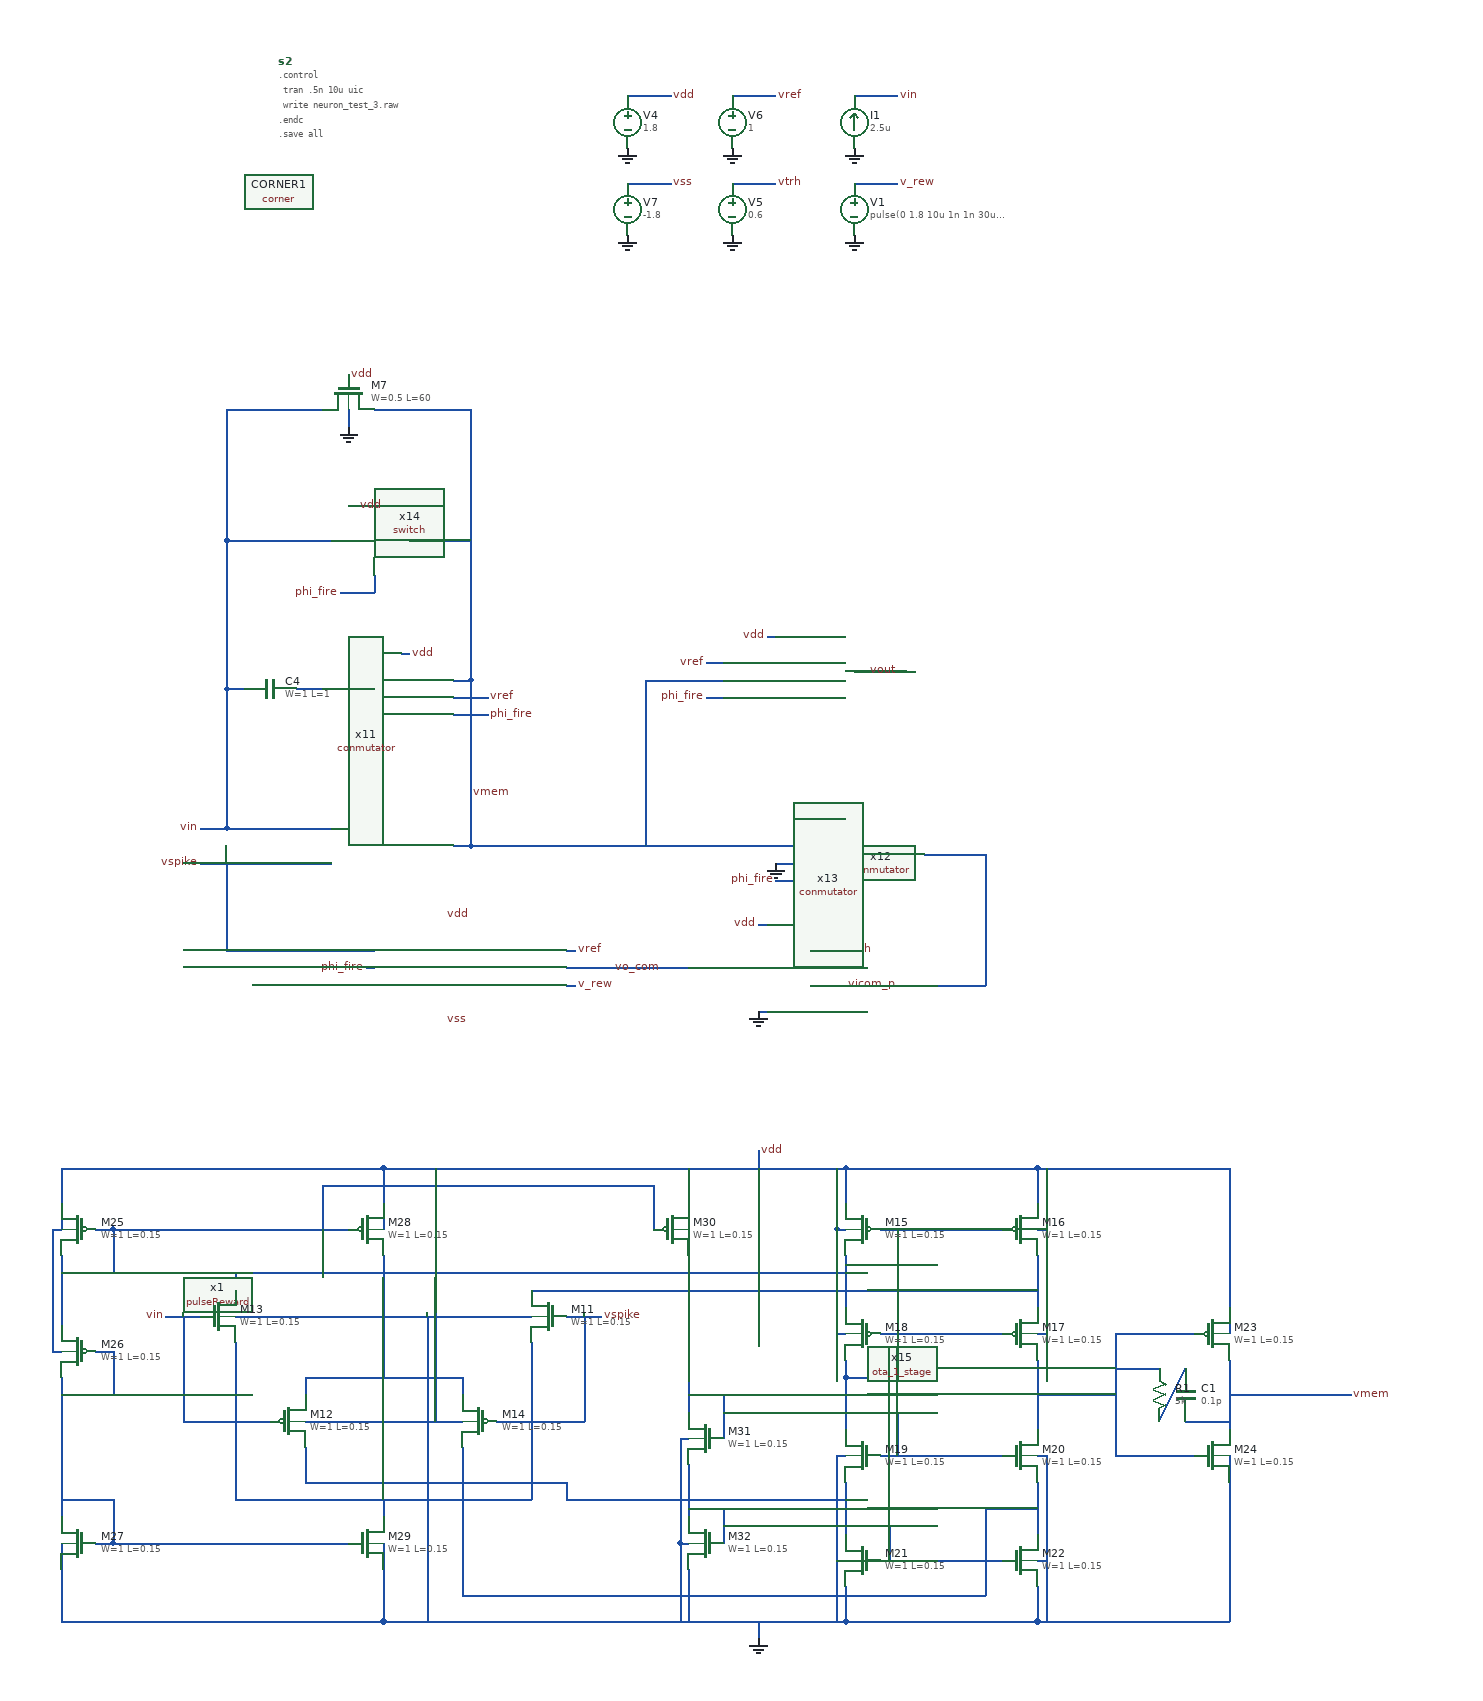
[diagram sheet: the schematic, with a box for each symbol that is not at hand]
v {xschem version=3.4.5 file_version=1.2
}
G {}
K {}
V {}
S {}
E {}
B 2 -940 -540 -140 -140 {flags=graph
y1=0.6
y2=1.5
ypos1=0
ypos2=2
divy=5
subdivy=1
unity=1
x1=5e-12
x2=1e-05
divx=5
subdivx=1


dataset=-1
unitx=1
logx=0
logy=0
color=12
node=vout}
B 2 -940 -1340 -140 -940 {flags=graph
y1=0.075
y2=1.8
ypos1=0
ypos2=2
divy=5
subdivy=1
unity=1
x1=5e-12
x2=1e-05
divx=5
subdivx=1


dataset=-1
unitx=1
logx=0
logy=0
color=7
node=vmem}
B 2 -940 -1740 -140 -1340 {flags=graph
y1=0.26

ypos1=0
ypos2=2
divy=5
subdivy=1
unity=1
x1=5e-12
x2=1e-05
divx=5
subdivx=1


dataset=-1
unitx=1
logx=0
logy=0
color=4
node=vspike
y2=1.6}
B 2 -940 -940 -140 -540 {flags=graph
y1=0.085
y2=2.1
ypos1=0
ypos2=2
divy=5
subdivy=1
unity=1
x1=5e-12
x2=1e-05
divx=5
subdivx=1


dataset=-1
unitx=1
logx=0
logy=0

color=10
node=vin}
B 2 -2780 -1340 -1980 -940 {flags=graph
y1=-0.056
y2=1.5
ypos1=0
ypos2=2
divy=5
subdivy=1
unity=1
x1=5e-12
x2=1e-05
divx=5
subdivx=1


dataset=-1
unitx=1
logx=0
logy=0


color="4 5"
node="vicom_p
vtrh"}
B 2 -2780 -985 -1980 -585 {flags=graph
y1=4.9e-05
y2=1.9
ypos1=0
ypos2=2
divy=5
subdivy=1
unity=1
x1=5e-12
x2=1e-05
divx=5
subdivx=1


dataset=-1
unitx=1
logx=0
logy=0



color=6
node=vo_com}
B 2 -2780 -610 -1980 -210 {flags=graph
y1=-0.096
y2=1.9
ypos1=0
ypos2=2
divy=5
subdivy=1
unity=1
x1=5e-12
x2=1e-05
divx=5
subdivx=1


dataset=-1
unitx=1
logx=0
logy=0




color=8
node=phi_fire}
B 2 -2780 -1740 -1980 -1340 {flags=graph
y1=0
y2=1.8
ypos1=0
ypos2=2
divy=5
subdivy=1
unity=1
x1=5e-12
x2=1e-05
divx=5
subdivx=1


dataset=-1
unitx=1
logx=0
logy=0


color=12
node=v_rew}
N -1360 -250 -1330 -250 {
lab=vo_com}
N -1190 -270 -1150 -270 {
lab=vtrh}
N -1250 -300 -1240 -300 {
lab=vdd}
N -1310 -560 -1290 -560 {
lab=phi_fire}
N -1310 -600 -1290 -600 {
lab=vref}
N -1140 -590 -1120 -590 {
lab=vout}
N -1660 -610 -1650 -610 {
lab=vdd}
N -1600 -560 -1560 -560 {
lab=vref}
N -1600 -580 -1580 -580 {
lab=vmem}
N -1600 -540 -1560 -540 {
lab=phi_fire}
N -1780 -570 -1750 -570 {
lab=#net1}
N -1580 -850 -1580 -580 {
lab=vmem}
N -1860 -740 -1860 -570 {
lab=vin}
N -1860 -570 -1840 -570 {
lab=vin}
N -1860 -850 -1860 -740 {
lab=vin}
N -1690 -700 -1690 -680 {
lab=phi_fire}
N -1730 -680 -1690 -680 {
lab=phi_fire}
N -1580 -580 -1580 -390 {
lab=vmem}
N -1860 -570 -1860 -410 {
lab=vin}
N -1860 -410 -1740 -410 {
lab=vin}
N -1890 -410 -1860 -410 {
lab=vin}
N -1400 -1250 -1350 -1250 {
lab=vdd}
N -1140 -1250 -1090 -1250 {
lab=vin}
N -1280 -1150 -1230 -1150 {
lab=vtrh}
N -1280 -1250 -1230 -1250 {
lab=vref}
N -1190 -230 -990 -230 {
lab=vicom_p}
N -1230 -370 -1210 -370 {
lab=GND}
N -1230 -350 -1210 -350 {
lab=phi_fire}
N -1230 -390 -1210 -390 {
lab=vmem}
N -1160 -420 -1150 -420 {
lab=vdd}
N -1410 -390 -1230 -390 {
lab=vmem}
N -1060 -380 -990 -380 {
lab=vicom_p}
N -990 -380 -990 -230 {
lab=vicom_p}
N -1650 -740 -1580 -740 {
lab=vmem}
N -1860 -740 -1740 -740 {
lab=vin}
N -1720 -780 -1710 -780 {
lab=vdd}
N -1120 -590 -1080 -590 {
lab=vout}
N -1600 -390 -1580 -390 {
lab=vmem}
N -1380 -580 -1380 -390 {
lab=vmem}
N -1380 -580 -1290 -580 {
lab=vmem}
N -1580 -390 -1410 -390 {
lab=vmem}
N -1240 -630 -1230 -630 {
lab=vdd}
N -1400 -1150 -1350 -1150 {
lab=vss}
N -1250 -200 -1240 -200 {
lab=GND}
N -1890 -370 -1740 -370 {
lab=vspike}
N -1860 -370 -1860 -270 {
lab=vspike}
N -1860 -270 -1690 -270 {
lab=vspike}
N -1470 -250 -1360 -250 {
lab=vo_com}
N -1470 -270 -1460 -270 {
lab=vref}
N -1700 -250 -1690 -250 {
lab=phi_fire}
N -1720 -890 -1720 -870 {
lab=GND}
N -1860 -890 -1750 -890 {
lab=vin}
N -1860 -890 -1860 -850 {
lab=vin}
N -1690 -890 -1580 -890 {
lab=vmem}
N -1580 -890 -1580 -850 {
lab=vmem}
N -1140 -1150 -1090 -1150 {
lab=v_rew}
N -1470 -230 -1460 -230 {
lab=v_rew}
N -1770 220 -1770 240 {
lab=#net2}
N -1770 220 -1590 220 {
lab=#net2}
N -1590 220 -1590 240 {
lab=#net2}
N -1850 180 -1850 360 {
lab=#net3}
N -1510 180 -1510 360 {
lab=#net3}
N -1850 360 -1510 360 {
lab=#net3}
N -1930 150 -1890 150 {
lab=vin}
N -1910 150 -1910 270 {
lab=vin}
N -1910 270 -1810 270 {
lab=vin}
N -1550 270 -1450 270 {
lab=vspike}
N -1450 150 -1450 270 {
lab=vspike}
N -1470 150 -1430 150 {
lab=vspike}
N -1680 80 -1680 220 {
lab=#net2}
N -1680 -20 -1680 20 {
lab=vdd}
N -1680 360 -1680 380 {
lab=#net3}
N -1150 80 -1150 140 {
lab=#net4}
N -930 80 -930 140 {
lab=#net5}
N -1110 50 -970 50 {
lab=#net4}
N -1150 -20 -1150 20 {
lab=vdd}
N -1150 -20 -930 -20 {
lab=vdd}
N -930 -20 -930 20 {
lab=vdd}
N -1150 220 -1110 220 {
lab=#net6}
N -1150 200 -1150 220 {
lab=#net6}
N -1150 340 -1150 400 {
lab=#net7}
N -930 340 -930 400 {
lab=#net8}
N -1150 220 -1150 280 {
lab=#net6}
N -930 200 -930 280 {
lab=#net9}
N -1150 460 -1150 500 {
lab=GND}
N -1150 500 -930 500 {
lab=GND}
N -930 460 -930 500 {
lab=GND}
N -1110 310 -970 310 {
lab=#net10}
N -1110 430 -970 430 {
lab=#net11}
N -1350 500 -1150 500 {
lab=GND}
N -1680 440 -1680 500 {
lab=GND}
N -1680 500 -1350 500 {
lab=GND}
N -1510 120 -930 120 {
lab=#net5}
N -1850 100 -1850 120 {
lab=#net4}
N -1850 100 -1170 100 {
lab=#net4}
N -1170 100 -1150 100 {
lab=#net4}
N -1150 90 -1090 90 {
lab=#net4}
N -1090 50 -1090 90 {
lab=#net4}
N -1770 300 -1770 340 {
lab=#net7}
N -1770 340 -1470 340 {
lab=#net7}
N -1470 360 -1150 360 {
lab=#net7}
N -1590 300 -1590 470 {
lab=#net8}
N -1590 470 -990 470 {
lab=#net8}
N -990 380 -990 470 {
lab=#net8}
N -1680 -20 -1150 -20 {
lab=vdd}
N -1250 -40 -1250 -20 {
lab=vdd}
N -1250 500 -1250 520 {
lab=GND}
N -1110 170 -970 170 {
lab=#net6}
N -1090 170 -1090 220 {
lab=#net6}
N -1110 220 -1090 220 {
lab=#net6}
N -840 170 -840 310 {
lab=#net9}
N -930 -20 -710 -20 {
lab=vdd}
N -710 -20 -710 140 {
lab=vdd}
N -930 500 -710 500 {
lab=GND}
N -710 340 -710 500 {
lab=GND}
N -710 200 -710 280 {
lab=vmem}
N -710 240 -570 240 {
lab=vmem}
N -1850 150 -1510 150 {
lab=GND}
N -1630 150 -1630 500 {
lab=GND}
N -1770 270 -1590 270 {
lab=vdd}
N -1620 -20 -1620 270 {
lab=vdd}
N -1160 50 -1150 50 {
lab=vdd}
N -1160 -20 -1160 50 {
lab=vdd}
N -1160 50 -1160 170 {
lab=vdd}
N -1160 170 -1150 170 {
lab=vdd}
N -930 170 -920 170 {
lab=vdd}
N -920 -20 -920 170 {
lab=vdd}
N -930 50 -920 50 {
lab=vdd}
N -1160 310 -1150 310 {
lab=GND}
N -1160 310 -1160 500 {
lab=GND}
N -1160 430 -1150 430 {
lab=GND}
N -930 310 -920 310 {
lab=GND}
N -920 310 -920 500 {
lab=GND}
N -930 430 -920 430 {
lab=GND}
N -1100 390 -1100 430 {
lab=#net11}
N -990 370 -930 370 {
lab=#net8}
N -990 370 -990 380 {
lab=#net8}
N -710 140 -710 170 {
lab=vdd}
N -710 310 -710 340 {
lab=GND}
N -2010 50 -1990 50 {
lab=#net12}
N -1990 50 -1990 100 {
lab=#net12}
N -2050 100 -1990 100 {
lab=#net12}
N -2050 80 -2050 160 {
lab=#net12}
N -2050 220 -2050 380 {
lab=#net13}
N -2050 240 -1990 240 {
lab=#net13}
N -1990 190 -1990 240 {
lab=#net13}
N -2010 190 -1990 190 {
lab=#net13}
N -2050 440 -2050 500 {
lab=GND}
N -2050 360 -1990 360 {
lab=#net13}
N -1990 360 -1990 410 {
lab=#net13}
N -2010 410 -1990 410 {
lab=#net13}
N -2050 410 -2050 440 {
lab=GND}
N -2060 190 -2050 190 {
lab=vdd}
N -2060 50 -2060 190 {
lab=vdd}
N -2060 50 -2050 50 {
lab=vdd}
N -2050 20 -2050 50 {
lab=vdd}
N -2050 -20 -2050 20 {
lab=vdd}
N -1680 20 -1680 50 {
lab=vdd}
N -1680 410 -1680 440 {
lab=GND}
N -1750 0 -1750 50 {
lab=#net12}
N -1750 0 -1370 0 {
lab=#net12}
N -1370 0 -1370 50 {
lab=#net12}
N -1330 -20 -1330 20 {
lab=vdd}
N -1330 20 -1330 50 {
lab=vdd}
N -1470 340 -1470 360 {
lab=#net7}
N -1330 80 -1330 260 {
lab=#net10}
N -1330 320 -1330 380 {
lab=#net11}
N -1330 440 -1330 500 {
lab=GND}
N -1330 370 -1290 370 {
lab=#net11}
N -1290 370 -1290 410 {
lab=#net11}
N -1290 390 -1100 390 {
lab=#net11}
N -1330 240 -1290 240 {
lab=#net10}
N -1290 240 -1290 290 {
lab=#net10}
N -1090 260 -1090 310 {
lab=#net10}
N -1270 260 -1090 260 {
lab=#net10}
N -1290 260 -1270 260 {
lab=#net10}
N -1340 290 -1330 290 {
lab=GND}
N -1340 290 -1340 410 {
lab=GND}
N -1340 410 -1330 410 {
lab=GND}
N -1340 410 -1340 500 {
lab=GND}
N -2050 -20 -1680 -20 {
lab=vdd}
N -1990 50 -1720 50 {
lab=#net12}
N -2050 500 -1680 500 {
lab=GND}
N -1990 410 -1720 410 {
lab=#net13}
N -930 240 -840 240 {
lab=#net9}
N -840 310 -750 310 {
lab=#net9}
N -840 170 -750 170 {
lab=#net9}
N -840 210 -820 210 {
lab=#net9}
N -730 270 -710 270 {
lab=vmem}
N -820 210 -790 210 {
lab=#net9}
N -790 270 -760 210 {
lab=#net14}
N -760 270 -730 270 {
lab=vmem}
C {devices/code_shown.sym} -1800 -1290 0 0 {name=s2 only_toplevel=false value="
.control
 tran .5n 10u uic
 write neuron_test_3.raw
.endc
.save all" }
C {sky130_fd_pr/corner.sym} -1800 -1140 0 0 {name=CORNER1 only_toplevel=true corner=tt}
C {devices/lab_wire.sym} -1610 -310 0 1 {name=p48 sig_type=std_logic lab=vdd}
C {devices/lab_wire.sym} -1360 -250 0 0 {name=p49 sig_type=std_logic lab=vo_com}
C {devices/lab_wire.sym} -1150 -270 0 1 {name=p50 sig_type=std_logic lab=vtrh}
C {devices/lab_wire.sym} -1250 -300 0 0 {name=p51 sig_type=std_logic lab=vdd}
C {devices/lab_wire.sym} -1890 -370 0 0 {name=p52 sig_type=std_logic lab=vspike}
C {devices/lab_wire.sym} -1310 -560 0 0 {name=p53 sig_type=std_logic lab=phi_fire}
C {devices/lab_wire.sym} -1310 -600 0 0 {name=p54 sig_type=std_logic lab=vref}
C {devices/lab_wire.sym} -1240 -630 0 0 {name=p56 sig_type=std_logic lab=vdd}
C {devices/lab_wire.sym} -1650 -610 0 1 {name=p57 sig_type=std_logic lab=vdd}
C {devices/lab_wire.sym} -1560 -540 0 1 {name=p58 sig_type=std_logic lab=phi_fire}
C {devices/lab_wire.sym} -1730 -680 0 0 {name=p59 sig_type=std_logic lab=phi_fire}
C {devices/lab_wire.sym} -1580 -450 0 1 {name=p60 sig_type=std_logic lab=vmem}
C {devices/gnd.sym} -1140 -1190 0 0 {name=l8 lab=GND}
C {devices/vsource.sym} -1400 -1220 0 0 {name=V4 value=1.8}
C {devices/gnd.sym} -1400 -1190 0 0 {name=l9 lab=GND}
C {devices/lab_wire.sym} -1350 -1250 0 1 {name=p61 sig_type=std_logic lab=vdd}
C {devices/lab_wire.sym} -1090 -1250 0 1 {name=p62 sig_type=std_logic lab=vin}
C {devices/vsource.sym} -1280 -1120 0 0 {name=V5 value=0.6}
C {devices/gnd.sym} -1280 -1090 0 0 {name=l10 lab=GND}
C {devices/lab_wire.sym} -1230 -1150 0 1 {name=p63 sig_type=std_logic lab=vtrh}
C {devices/vsource.sym} -1280 -1220 0 0 {name=V6 value=1}
C {devices/gnd.sym} -1280 -1190 0 0 {name=l11 lab=GND}
C {devices/lab_wire.sym} -1230 -1250 0 1 {name=p64 sig_type=std_logic lab=vref}
C {devices/lab_wire.sym} -1890 -410 0 0 {name=p65 sig_type=std_logic lab=vin}
C {devices/isource.sym} -1140 -1220 2 1 {name=I1 value=2.5u}
C {devices/lab_wire.sym} -1150 -230 2 0 {name=p66 sig_type=std_logic lab=vicom_p}
C {/home/user/Documentos/conmutator.sym} -1600 -510 0 1 {name=x11}
C {/home/user/Documentos/conmutator.sym} -1290 -530 0 0 {name=x12}
C {devices/lab_wire.sym} -1230 -350 0 0 {name=p67 sig_type=std_logic lab=phi_fire}
C {devices/lab_wire.sym} -1160 -420 0 0 {name=p68 sig_type=std_logic lab=vdd}
C {/home/user/Documentos/conmutator.sym} -1210 -320 0 0 {name=x13}
C {devices/gnd.sym} -1230 -370 1 1 {name=l12 lab=GND}
C {/home/user/Documentos/switch.sym} -1760 -680 0 0 {name=x14}
C {devices/lab_wire.sym} -1710 -780 0 1 {name=p69 sig_type=std_logic lab=vdd}
C {devices/lab_wire.sym} -1090 -590 0 0 {name=p70 sig_type=std_logic lab=vout}
C {devices/lab_wire.sym} -1560 -560 0 1 {name=p71 sig_type=std_logic lab=vref}
C {/home/user/Documentos/ota_1_stage.sym} -1240 -250 0 1 {name=x15}
C {devices/vsource.sym} -1400 -1120 0 0 {name=V7 value=-1.8}
C {devices/gnd.sym} -1400 -1090 0 0 {name=l13 lab=GND}
C {devices/lab_wire.sym} -1350 -1150 0 1 {name=p72 sig_type=std_logic lab=vss}
C {devices/gnd.sym} -1250 -200 0 1 {name=l14 lab=GND}
C {devices/lab_wire.sym} -1460 -270 0 1 {name=p1 sig_type=std_logic lab=vref}
C {devices/lab_wire.sym} -1700 -250 2 1 {name=p2 sig_type=std_logic lab=phi_fire}
C {sky130_fd_pr/cap_mim_m3_2.sym} -1810 -570 3 0 {name=C4 model=cap_mim_m3_2 W=1 L=1 MF=200 spiceprefix=X}
C {sky130_fd_pr/nfet_01v8.sym} -1720 -910 1 0 {name=M7
L=60
W=0.5
nf=1 mult=1
model=nfet_01v8
spiceprefix=X
}
C {devices/gnd.sym} -1720 -870 0 0 {name=l17 lab=GND}
C {devices/lab_wire.sym} -1610 -190 0 1 {name=p3 sig_type=std_logic lab=vss}
C {devices/lab_wire.sym} -1720 -930 0 1 {name=p4 sig_type=std_logic lab=vdd}
C {/home/user/Documentos/pulseReward.sym} -1580 -260 0 1 {name=x1}
C {devices/vsource.sym} -1140 -1120 0 0 {name=V1 value="pulse(0 1.8 10u 1n 1n 30u 60u)"}
C {devices/gnd.sym} -1140 -1090 0 0 {name=l2 lab=GND}
C {devices/lab_wire.sym} -1090 -1150 0 1 {name=p5 sig_type=std_logic lab=v_rew}
C {devices/lab_wire.sym} -1460 -230 0 1 {name=p6 sig_type=std_logic lab=v_rew}
C {sky130_fd_pr/pfet_01v8.sym} -1790 270 0 0 {name=M12
L=0.15
W=1
nf=1 mult=1
model=pfet_01v8
spiceprefix=X
}
C {sky130_fd_pr/nfet_01v8.sym} -1870 150 0 0 {name=M13
L=0.15
W=1  
nf=1 mult=1
model=nfet_01v8
spiceprefix=X
}
C {sky130_fd_pr/nfet_01v8.sym} -1490 150 0 1 {name=M11
L=0.15
W=1  
nf=1 mult=1
model=nfet_01v8
spiceprefix=X
}
C {sky130_fd_pr/pfet_01v8.sym} -1570 270 0 1 {name=M14
L=0.15
W=1
nf=1 mult=1
model=pfet_01v8
spiceprefix=X
}
C {sky130_fd_pr/pfet_01v8.sym} -1130 50 0 1 {name=M15
L=0.15
W=1
nf=1 mult=1
model=pfet_01v8
spiceprefix=X
}
C {sky130_fd_pr/pfet_01v8.sym} -950 50 0 0 {name=M16
L=0.15
W=1
nf=1 mult=1
model=pfet_01v8
spiceprefix=X
}
C {sky130_fd_pr/pfet_01v8.sym} -950 170 0 0 {name=M17
L=0.15
W=1
nf=1 mult=1
model=pfet_01v8
spiceprefix=X
}
C {sky130_fd_pr/pfet_01v8.sym} -1130 170 0 1 {name=M18
L=0.15
W=1
nf=1 mult=1
model=pfet_01v8
spiceprefix=X
}
C {sky130_fd_pr/nfet_01v8.sym} -1130 310 0 1 {name=M19
L=0.15
W=1  
nf=1 mult=1
model=nfet_01v8
spiceprefix=X
}
C {sky130_fd_pr/nfet_01v8.sym} -950 310 0 0 {name=M20
L=0.15
W=1  
nf=1 mult=1
model=nfet_01v8
spiceprefix=X
}
C {sky130_fd_pr/nfet_01v8.sym} -1130 430 0 1 {name=M21
L=0.15
W=1  
nf=1 mult=1
model=nfet_01v8
spiceprefix=X
}
C {sky130_fd_pr/nfet_01v8.sym} -950 430 0 0 {name=M22
L=0.15
W=1  
nf=1 mult=1
model=nfet_01v8
spiceprefix=X
}
C {devices/lab_wire.sym} -1430 150 0 1 {name=p19 sig_type=std_logic lab=vspike}
C {devices/lab_wire.sym} -1930 150 0 0 {name=p20 sig_type=std_logic lab=vin}
C {devices/lab_wire.sym} -1250 -40 0 1 {name=p21 sig_type=std_logic lab=vdd}
C {devices/gnd.sym} -1250 520 0 0 {name=l1 lab=GND}
C {sky130_fd_pr/pfet_01v8.sym} -730 170 0 0 {name=M23
L=0.15
W=1
nf=1 mult=1
model=pfet_01v8
spiceprefix=X
}
C {sky130_fd_pr/nfet_01v8.sym} -730 310 0 0 {name=M24
L=0.15
W=1  
nf=1 mult=1
model=nfet_01v8
spiceprefix=X
}
C {devices/lab_wire.sym} -570 240 0 1 {name=p22 sig_type=std_logic lab=vmem}
C {sky130_fd_pr/pfet_01v8.sym} -2030 50 0 1 {name=M25
L=0.15
W=1
nf=1 mult=1
model=pfet_01v8
spiceprefix=X
}
C {sky130_fd_pr/pfet_01v8.sym} -2030 190 0 1 {name=M26
L=0.15
W=1
nf=1 mult=1
model=pfet_01v8
spiceprefix=X
}
C {sky130_fd_pr/nfet_01v8.sym} -2030 410 0 1 {name=M27
L=0.15
W=1  
nf=1 mult=1
model=nfet_01v8
spiceprefix=X
}
C {sky130_fd_pr/pfet_01v8.sym} -1700 50 0 0 {name=M28
L=0.15
W=1
nf=1 mult=1
model=pfet_01v8
spiceprefix=X
}
C {sky130_fd_pr/nfet_01v8.sym} -1700 410 0 0 {name=M29
L=0.15
W=1  
nf=1 mult=1
model=nfet_01v8
spiceprefix=X
}
C {sky130_fd_pr/pfet_01v8.sym} -1350 50 0 0 {name=M30
L=0.15
W=1
nf=1 mult=1
model=pfet_01v8
spiceprefix=X
}
C {sky130_fd_pr/nfet_01v8.sym} -1310 290 0 1 {name=M31
L=0.15
W=1  
nf=1 mult=1
model=nfet_01v8
spiceprefix=X
}
C {sky130_fd_pr/nfet_01v8.sym} -1310 410 0 1 {name=M32
L=0.15
W=1  
nf=1 mult=1
model=nfet_01v8
spiceprefix=X
}
C {devices/capa.sym} -760 240 0 0 {name=C1
m=1
value=0.1p
footprint=1206
device="ceramic capacitor"}
C {devices/res.sym} -790 240 0 0 {name=R1
value=5k
footprint=1206
device=resistor
m=1}
